VERSION 5.8 ;
BUSBITCHARS "[]" ;
DIVIDERCHAR "/" ;
UNITS
  DATABASE MICRONS 1000 ;
END UNITS
MANUFACTURINGGRID 0.005 ;

SITE core
  CLASS CORE ;
  SIZE 0.2 BY 1.2 ;
END core

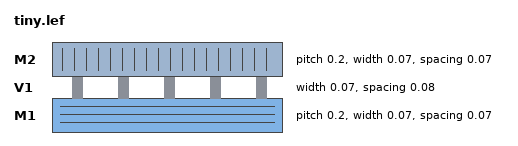
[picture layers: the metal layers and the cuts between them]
LAYER M1
  TYPE ROUTING ;
  DIRECTION HORIZONTAL ;
  PITCH 0.2 ;
  WIDTH 0.07 ;
  SPACING 0.07 ;
END M1

LAYER V1
  TYPE CUT ;
  WIDTH 0.07 ;
  SPACING 0.08 ;
END V1

LAYER M2
  TYPE ROUTING ;
  DIRECTION VERTICAL ;
  PITCH 0.2 ;
  WIDTH 0.07 ;
  SPACING 0.07 ;
END M2

VIA V12 DEFAULT
  LAYER M1 ;
    RECT -0.05 -0.035 0.05 0.035 ;
  LAYER V1 ;
    RECT -0.035 -0.035 0.035 0.035 ;
  LAYER M2 ;
    RECT -0.035 -0.05 0.035 0.05 ;
END V12

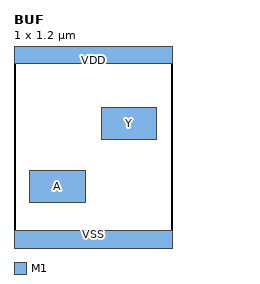
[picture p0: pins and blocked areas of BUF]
MACRO BUF
  CLASS CORE ;
  ORIGIN 0 0 ;
  SIZE 1.0 BY 1.2 ;
  SITE core ;
  PIN A
    DIRECTION INPUT ;
    USE SIGNAL ;
    PORT
      LAYER M1 ;
        RECT 0.1 0.25 0.45 0.45 ;
    END
  END A
  PIN Y
    DIRECTION OUTPUT ;
    USE SIGNAL ;
    PORT
      LAYER M1 ;
        RECT 0.55 0.65 0.9 0.85 ;
    END
  END Y
  PIN VDD
    DIRECTION INOUT ;
    USE POWER ;
    PORT
      LAYER M1 ;
        RECT 0 1.13 1.0 1.27 ;
    END
  END VDD
  PIN VSS
    DIRECTION INOUT ;
    USE GROUND ;
    PORT
      LAYER M1 ;
        RECT 0 -0.07 1.0 0.07 ;
    END
  END VSS
END BUF

END LIBRARY
